One B-rep face of a CAD part: STEP entity #105.
In plain terms, the planar face has unit normal (0, -1, 0).
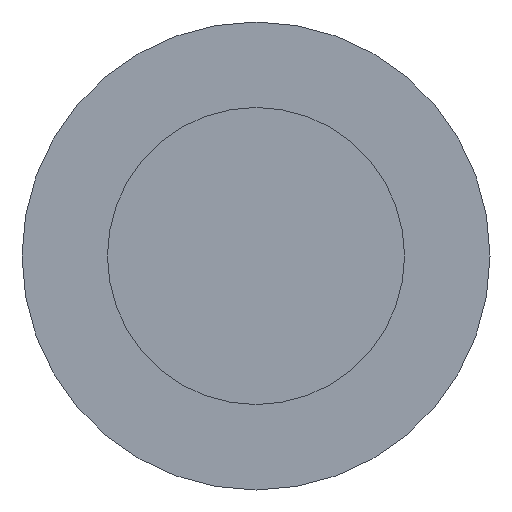
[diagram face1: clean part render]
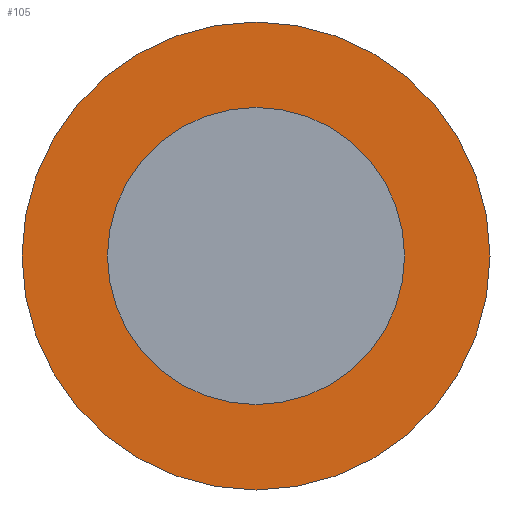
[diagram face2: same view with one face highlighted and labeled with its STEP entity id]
Its self-contained STEP definition (entity closure, numbers rounded to 3 decimals):
#22 = VERTEX_POINT('',#23);
#23 = CARTESIAN_POINT('',(64.,58.7,-207.));
#32 = CYLINDRICAL_SURFACE('',#33,5.);
#33 = AXIS2_PLACEMENT_3D('',#34,#35,#36);
#34 = CARTESIAN_POINT('',(59.,58.7,-207.));
#35 = DIRECTION('',(0.,-1.,-0.));
#36 = DIRECTION('',(1.,0.,0.));
#79 = EDGE_CURVE('',#22,#22,#80,.T.);
#80 = SURFACE_CURVE('',#81,(#86,#93),.PCURVE_S1.);
#81 = CIRCLE('',#82,5.);
#82 = AXIS2_PLACEMENT_3D('',#83,#84,#85);
#83 = CARTESIAN_POINT('',(59.,58.7,-207.));
#84 = DIRECTION('',(-0.,1.,0.));
#85 = DIRECTION('',(1.,0.,0.));
#86 = PCURVE('',#32,#87);
#87 = DEFINITIONAL_REPRESENTATION('',(#88),#92);
#88 = LINE('',#89,#90);
#89 = CARTESIAN_POINT('',(-0.,0.));
#90 = VECTOR('',#91,1.);
#91 = DIRECTION('',(-1.,0.));
#92 = ( GEOMETRIC_REPRESENTATION_CONTEXT(2) 
PARAMETRIC_REPRESENTATION_CONTEXT() REPRESENTATION_CONTEXT('2D SPACE',''
  ) );
#93 = PCURVE('',#94,#99);
#94 = PLANE('',#95);
#95 = AXIS2_PLACEMENT_3D('',#96,#97,#98);
#96 = CARTESIAN_POINT('',(59.,58.7,-207.));
#97 = DIRECTION('',(0.,1.,0.));
#98 = DIRECTION('',(0.,-0.,1.));
#99 = DEFINITIONAL_REPRESENTATION('',(#100),#104);
#100 = CIRCLE('',#101,5.);
#101 = AXIS2_PLACEMENT_2D('',#102,#103);
#102 = CARTESIAN_POINT('',(0.,0.));
#103 = DIRECTION('',(0.,1.));
#104 = ( GEOMETRIC_REPRESENTATION_CONTEXT(2) 
PARAMETRIC_REPRESENTATION_CONTEXT() REPRESENTATION_CONTEXT('2D SPACE',''
  ) );
#105 = ADVANCED_FACE('',(#106,#109),#94,.F.);
#106 = FACE_BOUND('',#107,.F.);
#107 = EDGE_LOOP('',(#108));
#108 = ORIENTED_EDGE('',*,*,#79,.T.);
#109 = FACE_BOUND('',#110,.F.);
#110 = EDGE_LOOP('',(#111));
#111 = ORIENTED_EDGE('',*,*,#112,.F.);
#112 = EDGE_CURVE('',#113,#113,#115,.T.);
#113 = VERTEX_POINT('',#114);
#114 = CARTESIAN_POINT('',(62.175,58.7,-207.));
#115 = SURFACE_CURVE('',#116,(#121,#128),.PCURVE_S1.);
#116 = CIRCLE('',#117,3.175);
#117 = AXIS2_PLACEMENT_3D('',#118,#119,#120);
#118 = CARTESIAN_POINT('',(59.,58.7,-207.));
#119 = DIRECTION('',(-0.,1.,0.));
#120 = DIRECTION('',(1.,0.,0.));
#121 = PCURVE('',#94,#122);
#122 = DEFINITIONAL_REPRESENTATION('',(#123),#127);
#123 = CIRCLE('',#124,3.175);
#124 = AXIS2_PLACEMENT_2D('',#125,#126);
#125 = CARTESIAN_POINT('',(0.,0.));
#126 = DIRECTION('',(0.,1.));
#127 = ( GEOMETRIC_REPRESENTATION_CONTEXT(2) 
PARAMETRIC_REPRESENTATION_CONTEXT() REPRESENTATION_CONTEXT('2D SPACE',''
  ) );
#128 = PCURVE('',#129,#134);
#129 = CYLINDRICAL_SURFACE('',#130,3.175);
#130 = AXIS2_PLACEMENT_3D('',#131,#132,#133);
#131 = CARTESIAN_POINT('',(59.,9.7,-207.));
#132 = DIRECTION('',(0.,-1.,-0.));
#133 = DIRECTION('',(1.,0.,0.));
#134 = DEFINITIONAL_REPRESENTATION('',(#135),#139);
#135 = LINE('',#136,#137);
#136 = CARTESIAN_POINT('',(-0.,-49.));
#137 = VECTOR('',#138,1.);
#138 = DIRECTION('',(-1.,0.));
#139 = ( GEOMETRIC_REPRESENTATION_CONTEXT(2) 
PARAMETRIC_REPRESENTATION_CONTEXT() REPRESENTATION_CONTEXT('2D SPACE',''
  ) );
